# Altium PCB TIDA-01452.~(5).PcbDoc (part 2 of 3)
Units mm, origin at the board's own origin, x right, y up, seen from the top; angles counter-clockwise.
Board outline 60 x 40 mm, 6 copper layers (Top Layer, IN1-GND, IN2, IN3-POWER, IN4-GND, Bottom Layer), stack 1.532 mm thick; 266 components, 172 nets, 850 pads, 525 vias.

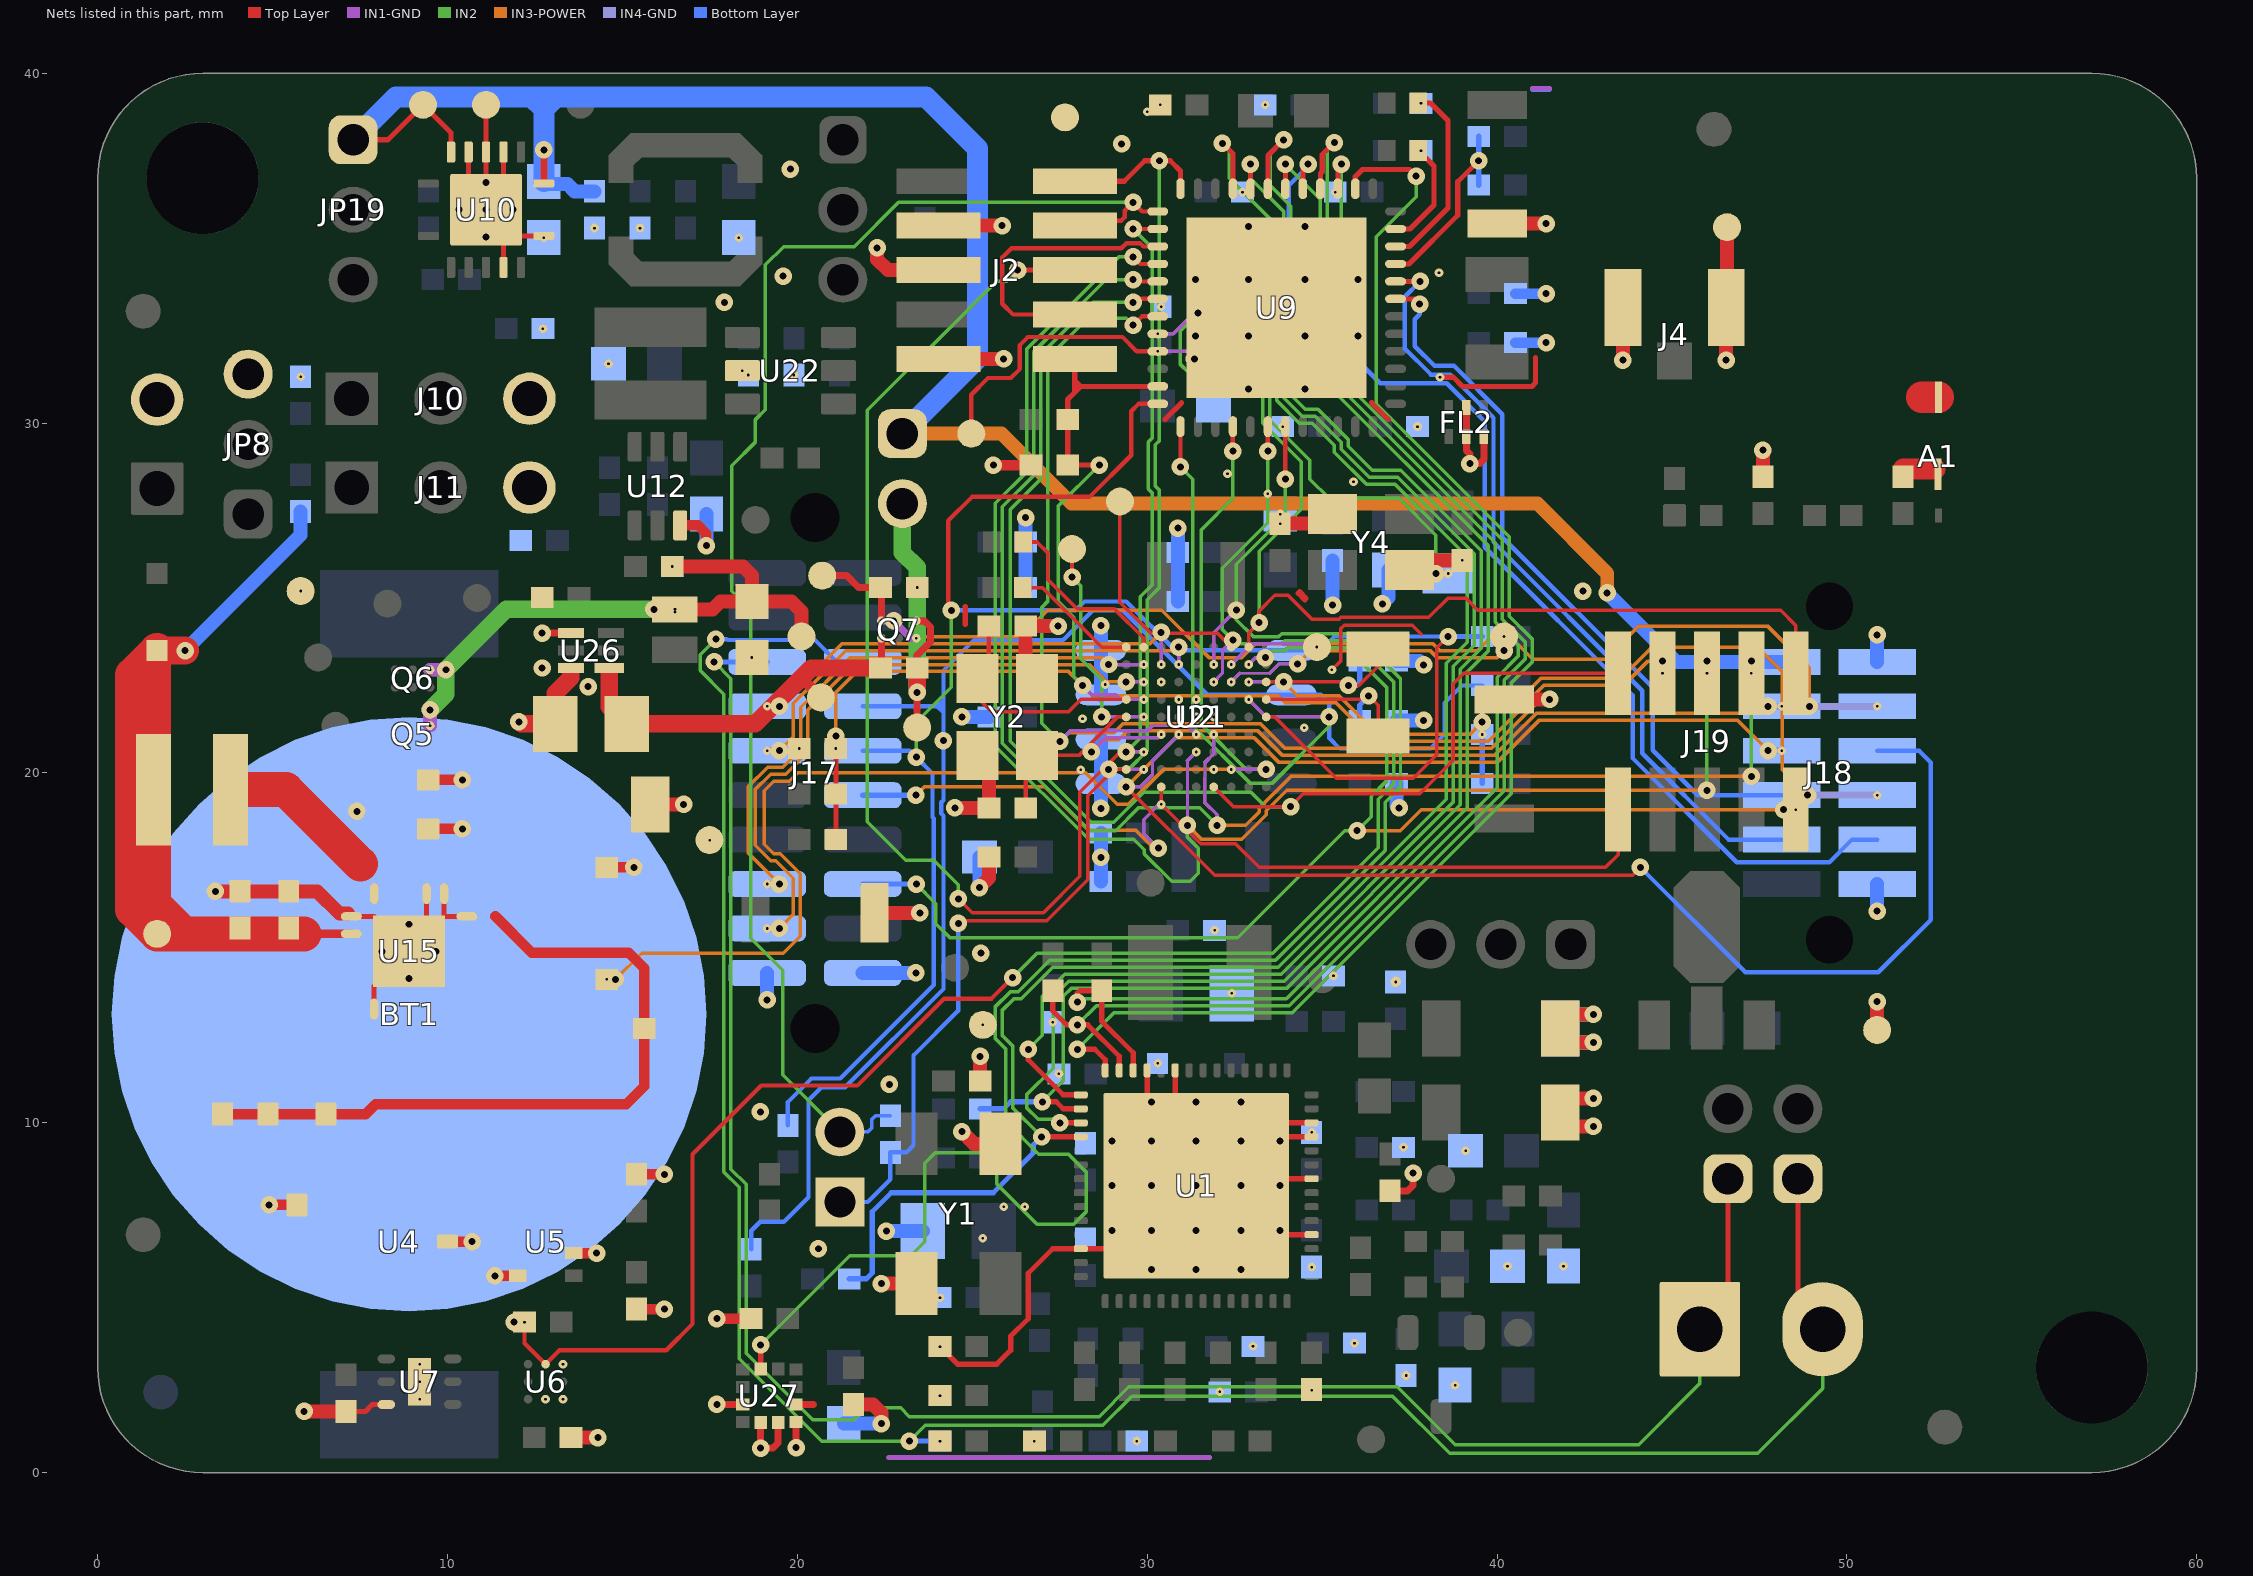
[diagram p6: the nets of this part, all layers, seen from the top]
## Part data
A1: "2.4GHz PCB Antenna.  There is nothing to buy or mount."
BT1: "Battery Holder, Retainer clip, SMT"
C1 C6: "CAP, CERM, 2.2 µF, 25 V, +/- 10%, X5R, 0402"
C2: "CAP, CERM, 2200 pF, 50 V, +/- 10%, X7R, 0402"
C3: "CAP, CERM, 0.47 µF, 16 V, +/- 10%, X5R, 0402"
C4 C9 C31 C32: "CAP, CERM, 1000 pF, 50 V, +/- 5%, C0G/NP0, 0402"
C5 C30 C35 C45 C47 C48 C49 C50 C51 C68 C84 C111 C112: "CAP, CERM, 0.1 µF, 50 V, +/- 10%, X7R, AEC-Q200 Grade 1, 0402"
C8: library part GRM1555C1H102JA01D, "CAP, CERM, 1000 pF, 50 V, +/- 5%, C0G/NP0, 0402"
C10 C14 C42 C43: "CAP, CERM, 16 pF, 50 V, +/- 5%, C0G/NP0, 0402"
C11: library part C1206C106K3RACTU, "DNI"
C12 C13: "CAP, CERM, 10 µF, 25 V, +/- 10%, X7R, 1206_190"
C15 C29: "CAP, CERM, 2.2 µF, 16 V, +/- 10%, X7R, 0805"
C16: "CAP, CERM, 100 pF, 50 V, +/- 5%, C0G/NP0, 0402"
C17: "CAP, CERM, 220 pF, 50 V, +/- 5%, C0G/NP0, 0402"
C18 C36 C37 C39 C40 C56 C57 C59 C61 C62 C71 C78 C80 C98 C100 C101: "CAP, CERM, 0.1 µF, 6.3 V, +/- 10%, X7R, 0402"
C19: "CAP, CERM, 390 pF, 50 V, +/- 5%, C0G/NP0, 0402"
C20 C21: "CAP, CERM, 0.22 µF, 16 V, +/- 10%, X7R, 0603"
C22: "CAP, CERM, 0.047 µF, 50 V, +/- 10%, X7R, 0402"
C23 C24: "CAP, CERM, 470 pF, 50 V, +/- 5%, C0G/NP0, 0402"
C25 C69: "CAP, CERM, 1 µF, 25 V, +/- 10%, X5R, 0402"
C26: "CAP, CERM, 33 pF, 50 V, +/- 5%, C0G/NP0, 0402"
C27 C34: "CAP, CERM, 0.022 µF, 50 V, +/- 10%, C0G/NP0, 0402"
C28: "CAP, CERM, 150 pF, 50 V, +/- 5%, C0G/NP0, 0402"
C33: "CAP, CERM, 0.01 µF, 50 V, +/- 10%, C0G/NP0, 0402"
C38 C58 C60 C75 C76 C85 C113: "CAP, CERM, 10 µF, 6.3 V, +/- 20%, X5R, 0603"
C41 C77 C79 C82: "CAP, CERM, 4.7 µF, 10 V, +/- 10%, X5R, 0402"
C44 C46 C65 C66: "CAP, CERM, 12 pF, 25 V, +/- 5%, C0G/NP0, 0402"
C55 C67 C110: library part C0402C103J5RACTU, "CAP, CERM, 0.01 µF, 50 V, +/- 5%, X7R, 0402"
C63 C64: library part GRM1555C1H9R0DA01D, "CAP, CERM, 9pF, 50V, +/- 0.5pF, C0G/NP0, 0402"
C70 C72: "CAP, CERM, 22 µF, 10 V, +/- 20%, X5R, 0603"
C81: "CAP, CERM, 0.01 µF, 50 V, +/- 5%, X7R, 0402"
C83: "CAP, CERM, 100 µF, 10 V, +/- 20%, X5R, 1206_190"
C86: "CAP, CERM, 10 µF, 10 V, +/- 10%, X7R, 0805"
CR1 CR3: "Red 621nm LED Indication - Discrete 1.8V 0402 (1005 Metric)"
CR2 CR4: "Green 569nm LED Indication - Discrete 1.9V 0402 (1005 Metric)"
D2 D4: "Diode, Schottky, 5V, 0.03A, SOD-323"
D3: "Diode, Schottky, 30 V, 0.2 A, SOD-323"
FL1: "Ferrite Bead, 1500 ohm @ 100 MHz, 0.5 A, 0603"
FL2: "Filter, BandPass, 2.45GHz, SMD"
J2 J19: "Header, 1.27mm, 5x2, Gold, SMT"
J4: library part U.FL-R-SMT-1, "Connector, Ultra-Mini Coaxial, SMD"
J5: "Terminal Block, 6A, 3.5mm Pitch, 2-Pos, TH"
J9: "Header, 100mil, 2x1, Tin, TH"
J10 J11: "Header, 100mil, 3x1, Tin, TH"
J17: "Receptacle, 50mil, 10x2, Gold, SMT"
J18: "Receptacle, 1.27mm, 6x2, Gold, SMT"
JP1 JP24 JP25 JP30: "Header, 2mm, 2x1, Tin, TH"
JP6 JP7 JP8 JP19: "Header, 2mm, 3x1, Tin, TH"
L1: "Inductor, Wirewound, 100 µH, 0.27 A, 1.4 ohm, SMD"
L2 L3: "Inductor, Multilayer, Ferrite, 4.7 µH, 0.3 A, 0.143 ohm, SMD"
L4: "Inductor, Multilayer, Ferrite, 10 µH, 0.11 A, 0.52 ohm, SMD"
L5: "Inductor, Shielded Drum Core, Ferrite, 10 µH, 1.25 A, 0.2 ohm, SMD"
L6: "Inductor, Shielded, Ferrite, 4.7 µH, 1.2 A, 0.14 ohm, SMD"
L7: "Inductor, Shielded Drum Core, Ferrite, 22uH, 0.5A, 0.525 ohm, SMD"
L8: "Inductor, Shielded, Ferrite, 4.7uH, 0.64A, 0.25 ohm, SMD"
Q1: library part "2SB1260T100R, Rohm", "Transistor, PNP, 80 V, 1 A, SOT-89"
Q4: library part "BC846BLT1G, ON Semiconductor", "Transistor, NPN, 65 V, 0.1 A, SOT-23"
Q5 Q6 Q7: "MOSFET, P-CH, -20 V, -1.6 A,"
R1: "RES, 20.0 k, 1%, 0.1 W, 0603"
R5: "RES, 402 k, 1%, 0.063 W, 0402"
R7 R15 R16 R24 R28 R44 R67: "RES, 100 k, 1%, 0.063 W, 0402"
R8: "RES, 4.02, 1%, 0.1 W, 0603"
R9: "RES, 8.25 k, 1%, 0.1 W, 0603"
R10: "RES, 5.11 k, 1%, 0.063 W, 0402"
R11: "RES, 30.1 k, 1%, 0.063 W, 0402"
R12: "RES, 1.10 k, 1%, 0.1 W, 0603"
R13 R14 R21 R22: "RES, 33.0 k, 0.1%, 0.063 W, 0402"
R17: "RES, 10.0, 1%, 0.1 W, 0603"
R18: "RES, 200 k, 1%, 0.063 W, 0402"
R19: "RES, 49.9 k, 1%, 0.063 W, 0402"
R20: "RES, 332 k, 1%, 0.063 W, 0402"
R23: "RES, 37.4 k, 1%, 0.063 W, 0402"
R25: "RES, 91.0 k, 0.1%, 0.1 W, 0603"
R26 R41 R45 R49 R56 R59 R68 R84 R87 R95 R100: library part CRCW04020000Z0ED, "RES, 0, 5%, 0.063 W, 0402"
R27 R31 R42 R43 R46 R54 R60 R80 R85 R86 R96 R118 R119 R122: "RES, 0, 5%, 0.063 W, 0402"
R29 R131 R132: library part CRCW0402100KFKED, "RES, 100 k, 1%, 0.063 W, 0402"
R30 R34 R39: "RES, 270, 1%, 0.0625W, 50V, 0402"
R32 R33 R37 R38: "RES, 680, 5%, 0.063 W, 0402"
R35 R36 R40 R109 R110: "RES, 10.0 k, 1%, 0.063 W, 0402"
R55 R93 R139: "RES, 1.00 M, 1%, 0.063 W, 0402"
R61: "RES, 6.65 M, 1%, 0.063 W, 0402"
R62: "RES, 2.37 M, 1%, 0.063 W, 0402"
R63 R90: "RES, 5.11 M, 1%, 0.063 W, 0402"
R64: "RES, 6.19 M, 1%, 0.063 W, 0402"
R65: "RES, 4.42 M, 1%, 0.063 W, 0402"
R88: "RES, 7.87 M, 1%, 0.063 W, 0402"
R89: "RES, 169 k, 1%, 0.063 W, 0402"
R91: library part CRCW04021M00FKED, "RES, 1.00 M, 1%, 0.063 W, 0402"
R140: "RES, 402, 1%, 0.063 W, 0402"
SW1 SW2 SW3: "SWITCH TACTILE SPST-NO 0.05A 12V"
TP1 TP2 TP4 TP5 TP6 TP8 TP9 TP10 TP11 TP12 TP13 TP14 TP15 TP16 TP18 TP19 TP20 TP21 TP22 TP23 TP24 TP25 TP26 TP27 TP28 TP29 TP30 TP32 TP33 TP34: library part TEST_POINT_ROUND_1.2, "Round Test Point, 1.2mm diam."
U1: "DAC8730, DAC8730"
U2: "Mixed-Signal Microcontroller, ZXH0080A"
U4: "Low Power, High Accuracy Digital Humidity Sensor with Temperature Sensor, DMB0006A"
U5: "Digital Pressure Sensor, LGA8-2X2_5MM_0_65"
U6: "Infrared Thermopile Sensor with Integrated Math Engine, YZF0008AEAE"
U7: "Ambient Light Sensor, DNP0006A"
U9: "SimpleLink Multistandard Wireless MCU, RGZ0048A"
U10: "Programmable Output Voltage Ultra-Low Power Buck Converter with up to 50mA / 200 mA Output Current, RGY0014A"
U12: "LOW INPUT VOLTAGE STEP-UP CONVERTER IN 6 PIN SC-70 PACKAGE, DCK0006A"
U15: "Ultra Low Power Boost Converter with Battery Management for Energy Harvester Applications, RGR0020A"
U21: "256K I2C CMOS Serial EEPROM"
U22: "1-Ohm SPDT ANALOG SWITCH 5-V/3.3-V SINGLE-CHANNEL 2:1 MULTIPLEXER/DEMULTIPLEXER, DBV0006A"
U26: "Ultra-Low Quiescent Current Synchronous Boost with Integrated LDO/Load Switch, DSE0006A"
U27: "Ultra-low-power high-performance 3-axis pico accelerometer"
Y1: "Crystal, 8 MHz, 10 pF, SMD"
Y2: "Crystal, 48MHz, 10pF, SMD"
Y3 Y5: "Crystal, 32.768 KHz, 7 pF, SMD"
Y4: "Crystal, 24 MHz, 9 pF, SMD"

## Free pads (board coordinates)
  round 3.2 hole 3.2 unplated paste-3.2 mask+0.075: 0(3,37) 0(57,3)

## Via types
v1: diameter 0.4/0.5/0.5/0.5/0.5/0.4 (per signal layer), hole 0.2, Top Layer to Bottom Layer, 266 vias
v2: diameter 0.25/0.25 (per signal layer), hole 0.075, Top Layer to IN1-GND, tented top, 102 vias
v3: diameter 0.5/0.5/0.5/0.5 (per signal layer), hole 0.2, IN1-GND to IN4-GND, 75 vias
v4: diameter 0.25/0.25 (per signal layer), hole 0.075, IN4-GND to Bottom Layer, tented bottom, 55 vias
v5: diameter 0.5, hole 0.2, Top Layer to Bottom Layer, 21 vias
v6: diameter 0.25/0.2 (per signal layer), hole 0.075, Top Layer to IN1-GND, tented top, 5 vias
v7: diameter 0.3, hole 0.075, IN4-GND to Bottom Layer, 1 vias

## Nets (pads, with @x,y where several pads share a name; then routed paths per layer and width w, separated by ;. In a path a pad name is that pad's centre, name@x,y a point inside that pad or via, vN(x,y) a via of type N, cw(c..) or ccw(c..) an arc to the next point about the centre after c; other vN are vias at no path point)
ANA_SSM.ANA1_1: J17.7 U2.C8 | length 13.1
  IN1-GND w0.1: v2(30.4,23.1) v3(30.4,24.02)
  IN3-POWER w0.1: v3(19.485,21.905) 21.28,23.7 30.08,23.7 v3(30.4,24.02)
  IN4-GND w0.2: v4(19.135,21.905) v3(19.485,21.905)
ANA_SSM.ANA2_1: J17.9 U2.D8 | length 14
  IN1-GND w0.1: v2(30.9,23.1) v3(30.9,23.6)
  IN3-POWER w0.1: v3(19.485,20.635) 19.885,21.035 19.885,21.985 21.4,23.5 30.8,23.5 v3(30.9,23.6)
  IN4-GND w0.2: v4(19.135,20.635) v3(19.485,20.635)
BQ25505_VBAT_OK: R60.1 U2.G2 U9.40 | length 38.4
  Top Layer w0.125: v1(32.45,29.2) U9.40@32.45,29.9
  IN1-GND w0.1: v2(32.4,20.1) v3(33.4,20.1)
  IN1-GND w0.2: v2(14.55,14.1) v3(14.8,14.1)
  IN2 w0.1: v1(32.45,29.2) 32.45,27.849 31.55,26.949 31.55,21.384 32.834,20.1 v3(33.4,20.1)
  IN3-POWER w0.1: v3(14.8,14.1) 15.55,14.85 19.6,14.85 20.085,15.335 20.085,17.115 19.505,17.695 19.319,17.695 19.05,17.964 19.05,19.496 19.319,19.765 19.765,19.765 20,20 28.241,20 29.141,19.1 29.466,19.1 30.466,20.1 v3(33.4,20.1)
BUS+: J5.2 J17.6 JP24.1 R19.1 | length 66.8
  Top Layer w0.15: JP24.1@48.6,8.4 48.6,4.805 J5.2@49.305,4.1
  IN2 w0.1: v1(17.67,23.825) 17.22,23.375 17.22,22.93 17.9,22.25 17.9,8.593 18.338,8.156 18.338,3.259 20.696,0.9 v1(23.2,0.9) 23.65,1.35 28.521,1.35 28.729,1.35 29.566,2.188 37.012,2.188 38.65,0.55 47.45,0.55 49.305,2.405 J5.2@49.305,4.1
  Bottom Layer w0.125: v1(17.67,23.825) 17.985,23.825 18.01,23.8 20.5,23.8 21.125,23.175 J17.6@21.865,23.175
  Bottom Layer w0.15: v1(23.2,0.9) R19.1@24.075,0.9
BUS-: J5.1 J17.5 JP25.1 | length 57.9
  Top Layer w0.15: J5.1@45.8,4.1 46.6,4.9 JP25.1@46.6,8.4
  IN2 w0.1: v1(17.62,23.175) 18.1,22.695 18.1,8.676 18.538,8.238 18.538,3.412 20.44,1.51 21.61,1.51 21.95,1.85 22.95,1.85 23.2,1.6 28.625,1.6 29.475,2.45 37.15,2.45 38.8,0.8 44.05,0.8 45.8,2.55 J5.1@45.8,4.1
  Bottom Layer w0.15: v1(17.62,23.175) J17.5@19.135,23.175
CC2650_BSL: J18.10 U9.17 | length 31.6
  Top Layer w0.15: U9.17@34.45,36.7 34.45,37.25 v1(34.6,37.4)
  Bottom Layer w0.125: v1@34.6,37.35 34.05,36.8 34.05,33.75 36.662,31.138 38.561,31.138 39.65,30.048 39.65,26.45 43.875,22.225 43.875,20.425 46.85,17.45 49.5,17.45 50.145,18.095 J18.10@50.865,18.095
CC2650_BUTTON_4: R39.2 R40.2 U9.9 | length 5.6
  Top Layer w0.15: U9.9@37.1,34.55 37.484,34.55 38.875,35.941 38.875,36.9 v1(39.475,37.5)
  Bottom Layer w0.15: R40.2@39.475,36.8 v1(39.475,37.5) R39.2@39.475,38.2
CC2650_DAC8730_IRQ: R131.2 U1.26 U9.16 | length 40.7
  Top Layer w0.15: v1(28,13.45) 28,13.7 28.075,13.775 R131.2@28.7,13.775 28.7,12.9 29.6,12 U1.26@29.6,11.5 ; U9.16@34.95,36.7 34.95,37.134 35,37.184 35,37.67 v1(35.35,38.02)
  IN2 w0.1: v1(28,13.45) 28.1,13.55 33.98,13.55 40.004,19.574 40.004,22.739 40.6,23.334 40.6,23.666 39.95,24.316 39.95,26.584 35.15,31.384 35.15,37.82 v1(35.35,38.02)
CC2650_DAC8730_SPI_CLK: U1.29 U9.20 | length 40.5
  Top Layer w0.15: v1(26.6,12.1) 26.6,11.8 27.6,10.8 U1.29@28.1,10.8 ; U9.20@32.95,36.7 v1(32.95,37.4)
  IN2 w0.1: v1(26.6,12.1) 27,12.5 27,13.61 27.64,14.25 33.831,14.25 38.75,19.169 38.75,23.051 39.35,23.651 39.35,26.266 37.166,28.45 36.351,28.45 35.55,29.251 35.55,29.449 34.799,30.2 34.43,30.2 33.9,30.73 33.9,36.05 32.95,37 v1(32.95,37.4)
CC2650_DAC8730_SPI_CS: R29.2 U1.32 U9.21 | length 52.7
  Top Layer w0.15: v1(26.98,9.6) U1.32@28.1,9.6 ; v1(32.15,38) 32.45,37.7 U9.21@32.45,36.7
  IN2 w0.1: v1(26.98,9.6) 26.15,10.43 26.15,12.203 25.85,12.503 25.85,13.21 26.19,13.55 26.399,13.55 27.299,14.45 33.749,14.45 38.55,19.251 38.55,23.134 39.15,23.734 39.15,26.183 37.083,28.25 36.269,28.25 35.35,29.169 35.35,29.366 34.716,30 34.347,30 33.7,30.647 33.7,35.65 32.35,37 32.35,37.8 v1(32.15,38)
  Bottom Layer w0.15: R29.2@21.483,5.539 21.97,5.539 22.14,5.709 22.14,7.457 22.683,8 25.6,8 26.74,9.14 26.74,9.36 v1(26.98,9.6)
CC2650_DAC8730_SPI_MISO: R28.2 U1.30 U9.18 | length 41.8
  Top Layer w0.15: v1(27,10.6) 27.4,10.6 27.6,10.4 U1.30@28.1,10.4 ; U9.18@33.95,36.7 v1(33.95,37.4)
  IN2 w0.1: v1(27,10.6) 27.6,11.2 27.6,13.616 27.834,13.85 33.997,13.85 39.15,19.003 39.15,22.886 39.75,23.486 39.75,26.501 34.95,31.301 34.95,36.4 v1(33.95,37.4)
  Bottom Layer w0.15: R28.2@25.225,10.4 25.9,10.4 26.1,10.6 v1(27,10.6)
CC2650_DAC8730_SPI_MOSI: U1.31 U9.19 | length 43.3
  Top Layer w0.15: v1(27.5,10) U1.31@28.1,10 ; U9.19@33.45,36.7 33.45,37.65 v1(33.9,38.1)
  IN2 w0.1: v1(27.5,10) 27.4,10.1 26.881,10.1 26.562,10.419 26.562,10.812 27.312,11.562 27.312,13.611 27.751,14.05 33.914,14.05 38.95,19.086 38.95,22.969 39.55,23.569 39.55,26.349 37.249,28.65 36.434,28.65 35.75,29.334 35.75,29.531 34.881,30.4 34.513,30.4 34.1,30.813 34.1,36.204 33.512,36.791 33.512,37.712 v1(33.9,38.1)
CC2650_DAC8730_UART_RX: R132.2 U1.27 U9.15 | length 39.5
  Top Layer w0.15: R132.2@27.3,13.775 27.3,13.2 27.7,12.8 v1(28,12.8) 28.3,12.8 29.2,11.9 U1.27@29.2,11.5 ; U9.15@35.45,36.7 35.45,37.3 v1(35.55,37.4)
  IN2 w0.1: v1(28,12.8) 28.55,13.35 34.063,13.35 40.204,19.492 40.204,22.656 40.8,23.251 40.8,23.749 40.15,24.399 40.15,26.667 35.55,31.267 v1(35.55,37.4)
CC2650_DAC8730_UART_TX: U1.28 U9.14 | length 39.1
  Top Layer w0.15: v1(28,12.1) 28.5,12.1 28.8,11.8 U1.28@28.8,11.5 ; U9.14@35.95,36.7 35.95,37.05 36.15,37.25 37.5,37.25 v1(37.69,37.06)
  IN2 w0.1: v1(28,12.1) 29.05,13.15 34.146,13.15 40.404,19.409 40.404,22.573 41,23.169 41,23.831 40.35,24.481 40.35,26.75 36.55,30.55 36.55,35.331 37.69,36.471 v1(37.69,37.06)
CC2650_FTDI_UART_RX: J18.7 U9.7 | length 20.9
  Top Layer w0.15: U9.7@37.1,33.55 37.64,33.55 v1(37.79,33.4)
  Bottom Layer w0.125: v1(37.79,33.4) 37.79,33.11 37.65,32.97 37.65,32.2 38.212,31.638 38.768,31.638 40.15,30.255 40.15,26.739 44.45,22.439 44.45,20.65 45.735,19.365 J18.7@48.135,19.365
CC2650_FTDI_UART_TX: J18.9 U9.8 | length 22.5
  Top Layer w0.15: U9.8@37.1,34.05 v1(37.8,34.05)
  Bottom Layer w0.125: v1(37.8,34.05) 37.362,33.612 37.362,32.134 38.109,31.388 38.664,31.388 39.9,30.152 39.9,26.6 44.15,22.35 44.15,20.561 46.616,18.095 J18.9@48.135,18.095
CC2650_GPS_I2C_SCL: J17.8 R109.2 R119.1 U2.H6 U9.37 U21.6 | length 58.8
  Top Layer w0.125: v1(30.95,28.75) U9.37@30.95,29.9
  IN1-GND w0.1: v2(32.9,22.1) 33.4,21.6 v1(35.2,21.6)
  IN2 w0.1: v1(30.95,28.75) 31.3,28.4 31.3,21.351 32.951,19.7 33.566,19.7 35.2,21.334 v1(35.2,21.6)
  Bottom Layer w0.125: R119.1@18.68,6.381 18.68,6.911 18.936,7.167 19.615,7.167 20.319,7.872 20.319,10.644 20.689,11.014 21.364,11.014 24.175,13.825 24.175,18.777 24.112,18.839 24.112,19.161 24.175,19.223 v1(24.175,20.925) 24.175,21.73 ; J17.8@21.865,21.905 24,21.905 ; R109.2@39.575,22.5 39,22.5 38.5,22 38.5,21.1 38.1,20.7 35.5,20.7 35.2,21 v1(35.2,21.6) 35.2,22 34.965,22.235 U21.6@34.125,22.235 31.715,22.235 29.3,24.65 28.45,24.65 27.6,23.8 25.05,23.8 24.175,22.925 24.175,22.08 ; 24,21.905 24.175,22.08 ; 24,21.905 24.175,21.905 ; 24,21.905 24.175,21.73 ; 24.175,21.73 24.175,21.905 ; 24.175,21.905 24.175,22.08
CC2650_GPS_I2C_SDA: J17.10 R110.2 R118.1 U2.J5 U9.36 U21.5 | length 55.3
  Top Layer w0.1: U2.J5@33.4,21.6 33.65,21.6 35.4,19.85 37.6,19.85 38.275,20.525 38.275,23.575 v1(38.6,23.9)
  Top Layer w0.125: v1(24.4,24.65) 24.307,24.743 24.307,27.207 24.99,27.89 28.35,27.89 29.54,29.08 29.54,30.34 29.75,30.55 U9.36@30.3,30.55
  IN2 w0.1: v1(23.4,20.45) 23.4,21.45 24.4,22.45 v1(24.4,24.65)
  Bottom Layer w0.125: R118.1@19.73,9.925 19.73,10.593 20.401,11.264 21.225,11.264 23.9,13.939 23.9,18.698 23.862,18.736 23.862,19.988 v1(23.4,20.45) 23.215,20.635 J17.10@21.865,20.635 ; v1(24.4,24.65) 27.955,24.65 28.205,24.9 29.404,24.9 30.799,23.505 U21.5@34.125,23.505 34.955,23.505 35.35,23.9 v1(38.6,23.9)
  Bottom Layer w0.15: v1(38.6,23.9) R110.2@39.575,23.9
CC2650_GPS_LIS_IRQ: U2.F8 U9.43 U27.12 | length 53.8
  Top Layer w0.125: v1(33.95,28.4) U9.43@33.95,29.9
  Top Layer w0.15: U27.12@18.95,2.963 v1(18.95,3.65)
  IN1-GND w0.1: v2(31.9,23.1) 31.9,24.007 v3(32.55,24.657)
  IN2 w0.1: v1(18.95,3.65) 21.501,6.201 23.239,6.201 23.64,6.602 23.64,8.848 23.942,9.15 25.366,9.15 25.7,8.816 25.7,8.25 26.85,7.1 27.9,7.1 28.25,7.45 28.25,8.6 27.75,9.1 26.9,9.1 25.95,10.05 25.95,12.12 25.65,12.42 25.65,13.31 26.09,13.75 26.316,13.75 27.216,14.65 33.666,14.65 36.8,17.784 36.8,19.166 37.24,19.606 37.24,22.693 35.953,23.98 33.844,23.98 33.764,23.9 33.034,23.9 32.55,24.384 v3(32.55,24.657) 32.55,25.969 33.95,27.369 v1(33.95,28.4)
CC2650_GPS_TMP_IRQ: R36.2 U2.F7 U6.C2 U9.42 | length 52.8
  Top Layer w0.125: v2(12.2,4.3) 12.2,3.7 U6.C2@12.8,3.1 13.2,3.5 16.25,3.5 17,4.25 17,9.1 18.965,11.065 21.715,11.065 24.2,13.55 25.55,13.55 v1(26.15,14.15) ; v1(33.45,29.2) U9.42@33.45,29.9
  IN1-GND w0.082: 32.15,22.85 32.15,23.5
  IN1-GND w0.1: v2(31.9,22.6) 32.15,22.85 ; 32.15,23.5 v3(32.45,23.8)
  IN1-GND w0.2: v3(11.9,4.3) v2(12.2,4.3)
  IN2 w0.1: v1(26.15,14.15) 26.85,14.85 33.583,14.85 36.6,17.867 36.6,19.249 37.04,19.689 37.04,22.61 35.87,23.78 33.927,23.78 33.847,23.7 32.55,23.7 v3(32.45,23.8) 32.15,24.1 32.15,25.851 33.45,27.151 v1(33.45,29.2)
CC2650_JTAG_TCK: J2.4 JP1.2 R100.2 U9.25 | length 42.4
  Top Layer w0.125: J2.4@27.93,35.645 28.075,35.79 29.26,35.79 29.36,35.89 29.36,36.07 v1(29.6,36.31) 29.86,36.05 U9.25@30.3,36.05
  IN2 w0.1: JP1.2@21.215,9.737 19.577,11.375 19.577,14.364 18.661,15.279 18.661,24.661 18.124,25.198 18.124,28.783 18.802,29.461 18.802,30.103 19.085,30.386 19.085,34.523 19.607,35.046 21.626,35.046 22.891,36.31 v1(29.6,36.31)
  Bottom Layer w0.1: JP1.2@21.215,9.737 22.013,9.737 22.126,9.85 22.126,10.095 22.234,10.204 R100.2@22.656,10.204
CC2650_JTAG_TDI: J2.8 U9.27 | length 8.2
  Top Layer w0.125: J2.8@27.93,33.105 26.165,33.105 25.857,33.413 25.857,34.737 26.12,35 29.26,35 29.398,35.138 29.802,35.138 29.89,35.05 U9.27@30.3,35.05
CC2650_JTAG_TDO: U2.B3 U9.26 | length 16.8
  Top Layer w0.125: v1(29.6,35.55) U9.26@30.3,35.55
  IN1-GND w0.1: v3(29.4,20.6) v2(29.9,20.6)
  IN2 w0.1: v3(29.4,20.6) 29.8,21 29.8,25.033 30.15,25.383 30.15,27.999 30.031,28.118 30.031,29.46 30.15,29.579 30.15,35 v1(29.6,35.55)
CC2650_JTAG_TMS: J2.2 U2.B2 U9.24 | length 23.3
  Top Layer w0.15: J2.2@27.93,36.915 29.345,36.915 29.93,37.5 v1(30.35,37.5) 30.66,37.5 30.95,37.21 U9.24@30.95,36.7
  IN1-GND w0.1: v3(28.9,20.1) v2(29.9,20.1)
  IN2 w0.1: v3(28.9,20.1) 29.466,20.1 30,20.634 30,24.95 30.35,25.3 30.35,28.082 30.231,28.201 30.231,29.377 30.35,29.496 v1(30.35,37.5)
CC2650_LED1_4: CR3.2 U9.10 | length 5.5
  Top Layer w0.15: U9.10@37.1,35.05 37.5,35.05 38.6,36.15 38.6,38.65 38.1,39.15 CR3.2@37.75,39.15
CC2650_LED2_4: CR4.2 U9.11 | length 3.1
  Top Layer w0.15: U9.11@37.1,35.55 37.511,35.55 38.2,36.239 38.2,37.35 CR4.2@37.75,37.8
CC2650_NRESET: C45.1 C68.1 J2.10 J18.8 R24.2 R30.1 R44.2 U2.B6 U9.35 | length 55.3
  Top Layer w0.15: R30.1@21.1,18.1 v2(21.1,20.7) ; C68.1@27.725,28.8 R44.2@27.725,30.1 27.725,30.675 27.93,30.88 ; C68.1@27.8,28.8 v1(28.63,28.8) ; J2.10@27.93,31.835 27.93,31.22 ; U9.35@30.3,31.05 28.1,31.05 ; 27.93,30.88 28.1,31.05 ; 27.93,30.88 27.93,31.22 ; 27.93,31.22 28.1,31.05
  IN1-GND w0.1: v3(28.15,22.5) 28.42,22.23 29.103,22.23 29.233,22.1 v2(29.9,22.1)
  IN1-GND w0.2: v2(21.1,20.7) v3(21.1,21.05)
  IN2 w0.1: v3(28.15,22.5) 27.9,22.75 27.9,24.45 27.45,24.9 27.45,27.62 v1(28.63,28.8)
  IN3-POWER w0.1: v3(21.1,21.05) 21.1,22.3 21.7,22.9 27.75,22.9 v3(28.15,22.5) 28.45,22.2 33.75,22.2 33.95,22 35.4,22 36.5,20.9 39.75,20.9 40.9,22.05 40.9,22.349 41.251,22.7 43.533,22.7 44.433,23.6 47.436,23.6 48.15,22.886 48.15,20.095 v3(48.88,19.365)
  IN4-GND w0.2: v3(48.88,19.365) v4(50.865,19.365)
CC2650_SSM_IRQ: J19.10 U2.H9 U9.32 | length 32.3
  Top Layer w0.1: U2.H9@32.9,23.6 32.9,24 v1(33.2,24.3) 33.2,24.63 33.645,25.075 34.025,25.075 34.7,24.4 35.484,24.4 35.534,24.45 38.05,24.45 38.6,25 39.1,25 39.45,24.65 48.105,24.65 48.54,24.215 J19.10@48.54,22.85
  IN1-GND w0.1: v2(30.3,32.55) 30.75,32.55 31.35,33.15 v3(31.45,33.15)
  IN2 w0.1: v3(31.45,33.15) 31.45,33.137 30.95,32.637 30.95,31.674 31.184,31.44 32.997,31.44 33.3,31.137 33.3,30 34.4,28.9 34.4,27.536 33.2,26.336 v1(33.2,24.3)
CC2650_SSM_SPI_CLK: J19.2 U2.F1 U9.30 | length 39.6
  Top Layer w0.1: U2.F1@31.9,19.6 32.46,19.04 v1(34.1,19.04) 34.46,19.4 37.786,19.4 38.75,20.364 38.75,22.55 39.05,22.85 J19.2@43.46,22.85
  Top Layer w0.125: v1(29.6,33.45) 29.7,33.55 U9.30@30.3,33.55
  IN2 w0.1: v1(29.6,33.45) 28.45,33.45 26.95,31.95 26.95,28.4 26.08,27.53 26.08,20.91 28.4,18.59 29.04,18.59 29.9,19.45 32.966,19.45 33.376,19.04 v1(34.1,19.04)
CC2650_SSM_SPI_CS: J19.4 U2.E4 U9.31 | length 38.5
  Top Layer w0.125: v1(29.6,32.8) 29.85,33.05 U9.31@30.3,33.05
  IN1-GND w0.082: 30.15,21.35 31.15,21.35
  IN1-GND w0.1: v3(27.5,20.9) 27.8,21.2 30,21.2 30.15,21.35 ; 31.15,21.35 v2(31.4,21.1)
  IN1-GND w0.2: v2(44.73,22.85) v3(44.73,23.2)
  IN2 w0.1: v3(27.5,20.9) 26.98,21.42 26.98,24.73 27.15,24.9 27.15,31.85 28.3,33 29.4,33 v1(29.6,32.8)
  IN3-POWER w0.1: v3(27.5,20.9) 27.75,21.15 29.051,21.15 29.301,21.4 33.25,21.4 33.95,20.7 39.833,20.7 41.1,21.967 41.1,22.266 41.334,22.5 43.616,22.5 44.316,23.2 v3(44.73,23.2)
CC2650_SSM_SPI_MISO: J19.6 U2.E3 U9.28 | length 47.6
  Top Layer w0.125: v1(29.6,34.75) 29.8,34.55 U9.28@30.3,34.55
  IN1-GND w0.082: v3(31.15,18.5) 31.15,20.35
  IN1-GND w0.1: 31.15,20.35 v2(31.4,20.6)
  IN1-GND w0.2: v2(46,22.85) v3(46,23.2)
  IN2 w0.1: v1(29.6,34.75) 29.184,34.75 26.55,32.116 26.55,28.6 25.66,27.71 25.66,20.764 28.324,18.1 29.616,18.1 29.916,17.799 29.916,17.684 30.701,16.9 31.225,16.9 31.459,17.134 31.459,17.853 31.15,18.162 v3(31.15,18.5) ; v3(46,19.5) v3(46,23.2)
  IN3-POWER w0.1: v3(31.15,18.5) 31.55,18.1 32.699,18.1 33.4,18.801 33.4,18.916 33.984,19.5 v3(46,19.5)
CC2650_SSM_SPI_MOSI: J19.8 U2.F4 U9.29 | length 46
  Top Layer w0.125: v1(29.6,34.1) 29.65,34.05 U9.29@30.3,34.05
  IN1-GND w0.082: 31.65,19.85 31.65,20.3
  IN1-GND w0.1: 31.65,19.85 31.65,19.15 32,18.8 v3(32,18.5) ; 31.65,20.3 31.9,20.55 v2(31.9,21.1)
  IN1-GND w0.2: v2(47.27,22.85) v3(47.27,23.2)
  IN2 w0.1: v1(29.6,34.1) 28.817,34.1 26.75,32.033 26.75,28.5 25.86,27.61 25.86,20.847 28.357,18.35 29.1,18.35 29.75,19 31.5,19 v3(32,18.5) ; v3(47.27,19.9) v3(47.27,23.2)
  IN3-POWER w0.1: v3(32,18.5) 32.816,18.5 33.2,18.884 33.2,18.999 34.101,19.9 v3(47.27,19.9)
DCDC_SW: L4.1 TP33.1 U9.33 | length 20.3
  Top Layer w0.125: TP33.1@24.97,29.7 24.97,30.81 25.45,31.29 26.1,31.29 26.36,31.55 26.36,32.23 26.59,32.46 29.29,32.46 29.7,32.05 v2(30.3,32.05)
  IN1-GND w0.1: v2(30.3,32.05) 31.14,32.05 v3(31.35,31.84)
  IN2 w0.1: v3@31.35,31.85 32.9,31.85 33.5,31.25 33.5,30.084 34.65,28.934 34.65,28.4 35.2,27.85 37.2,27.85 38.25,26.8 v3(38.25,25.7)
  IN4-GND w0.2: v3(38.25,25.7) v4(38.6,25.7)
EH_NEN: J18.4 Q7.A2 Q7.C1 R139.2 TP2.1 | length 35.8
  Top Layer w0.2: TP2.1@20.71,25.64 21.41,25.64 21.75,25.3 R139.2@22.375,25.3 ; v2(22.4,24.35) R139.2@22.4,25.3
  IN1-GND w0.2: v2(22.4,24.35) v3(22.75,24.35) 23.25,23.85 v2(23.4,23.85)
  IN3-POWER w0.1: v3(22.75,24.35) 23.2,23.9 26.4,23.9 27.15,24.65 30.416,24.65 31.766,23.3 32.7,23.3 33.1,23.7 38.167,23.7 38.367,23.5 39.45,23.5 39.85,23.9 40.366,23.9 41.016,23.25 43.1,23.25 44.05,24.2 47.733,24.2 48.93,23.003 v3(48.93,21.905)
  IN4-GND w0.2: v3(48.93,21.905) v4(50.865,21.905)
EH_VIN_7: C79.1 C80.1 D2.1 L7.1 R49.1 TP25.1 U15.2 | length 28.8
  Top Layer w0.25: 5.9,15.4 U15.2@7.25,15.4
  Top Layer w0.8: v1(2.5,23.5) D2.1@1.7,23.5 1.7,16.3 2.6,15.4
  Top Layer w1: D2.1@1.7,23.5 1,22.8 1,16.1 TP25.1@1.7,15.4 2.6,15.4 5.9,15.4
  Bottom Layer w0.4: v1(2.5,23.5) 5.8,26.8 R49.1@5.8,27.475
EH_VOUT_7: C85.1 L8.1 Q5.A1 Q6.A1 R140.2 TP29.1 | length 17.2
  Top Layer w0.4: R140.2@16.425,25.9 18.45,25.9 18.7,25.65 C85.1@18.7,24.9 ; v2(16.5,24.675) 17.575,24.675 17.8,24.9 C85.1@18.7,24.9 ; TP29.1@20.12,23.9 20.12,24.61 19.83,24.9 C85.1@18.7,24.9
  IN1-GND w0.4: v2(9.5,21.35) v3(9.5,21.8) ; v2(9.5,22.95) v3(9.95,22.95) ; v3(15.9,24.675) v2(16.5,24.675)
  IN2 w0.5: v3(9.5,21.8) 9.95,22.25 v3(9.95,22.95) 11.675,24.675 v3(15.9,24.675)
EH_VOUT_REG_6: C86.2 Q7.C2 R68.1 TP30.1 U26.1 | length 11.4
  Top Layer w0.2: 14.625,22.86 U26.1@14.625,23 ; R68.1@22.4,23 Q7.C2@22.4,23.85
  Top Layer w0.3: 20.11,22.72 TP30.1@20.67,22.16
  Top Layer w0.5: 14.625,22.86 14.625,21.891 C86.2@15.116,21.4 18.79,21.4 20.39,23 R68.1@22.375,23 R68.1@22.4,23
FTDI_UART1.RX_1: J18.5 U2.D4 | length 22.8
  IN1-GND w0.082: 30.15,19.946 30.15,20.35
  IN1-GND w0.1: v3(29.4,19.6) 29.804,19.6 30.15,19.946 ; 30.15,20.35 v2(30.9,21.1)
  IN3-POWER w0.1: v3(29.4,19.6) 30.8,21 33.066,21 33.766,20.3 39.999,20.3 41.199,21.5 46.885,21.5 v3(47.75,20.635)
  IN4-GND w0.2: v3(47.75,20.635) v4(48.135,20.635)
FTDI_UART1.TX_1: J18.3 U2.C4 | length 23.1
  IN1-GND w0.1: v3(28.4,20.6) 28.8,21 30.3,21 v2(30.4,21.1)
  IN3-POWER w0.1: v3(28.4,20.6) 28.75,20.95 29.184,20.95 29.434,21.2 33.167,21.2 33.867,20.5 39.916,20.5 41.116,21.7 47.545,21.7 v3(47.75,21.905)
  IN4-GND w0.2: v3(47.75,21.905) v4(48.135,21.905)
GND: A1.2 A1.3 BT1.1 C1.2 C2.2 C3.2 C4.2 C5.2 C6.2 C8.2 C9.2 C10.1 C11.2 C12.2 C13.2 C14.1 C15.1 C18.2 C19.2 C20.2 C21.2 C25.2 C26.2 C29.2 C30.2 C31.2 C33.2 C34.2 C35.2 C36.2 C37.2 C38.2 C39.2 C40.2 C41.2 C42.2 C43.2 C44.1 C45.2 C46.1 C47.2 C48.2 C49.2 C50.2 C51.2 C55.2 C56.2 C57.2 C58.2 C59.2 C60.2 C61.2 C62.1 C63.2 C64.2 C65.2 C66.2 C67.2 C68.2 C69.2 C70.2 C71.1 C72.2 C75.2 C76.2 C77.2 C78.2 C79.2 C80.2 C81.2 C82.2 C83.2 C84.2 C85.2 C86.1 C98.2 C100.2 C101.1 C110.2 C111.2 C112.2 C113.2 D3.2 FL2.2 FL2.5 FL2.6 J2.3 J2.5 J2.9 J4.2 J4.3 J9.2 J10.3 J11.3 J17.19 J17.20 J18.2 J18.12 JP8.3 R7.2 R11.1 R12.2 R17.1 R25.1 R26.2 R32.1 R33.1 R37.1 R38.1 R45.1 R56.2 R59.2 R63.1 R65.1 R67.2 R85.2 R87.1 R90.1 R93.1 R122.2 R139.1 SW1.1 SW2.1 SW3.1 TP9.1 TP10.1 TP15.1 TP19.1 TP23.1 TP26.1 TP34.1 U1.4 U1.8 U1.11 U1.12 U1.23 U1.25 U1.40 U1.57 U2.C7 U2.D6 U2.E5 U2.E6 U2.F2 U2.F5 U4.2 U5.1 U5.7 U6.A1 U6.A2 U6.C1 U7.3 U7.7 U9.49 U10.3 U10.4 U10.5 U10.12 U10.14 U10.15@11.1,36.1 U12.3 U15.1 U15.6 U15.15 U15.16 U15.17 U15.21 U21.1 U21.2 U21.3 U21.4 U22.2 U26.4 U26.6 U27.3 U27.5 U27.6 U27.7 U27.8 Y1.2 Y1.4 Y2.2 Y2.4 Y4.2 Y4.4 | length 192.6
  Top Layer w0.1: v6(35.28,22.95) 35.525,23.195 35.525,24.122 35.628,24.225 37.572,24.225 37.837,23.96
  Top Layer w0.15: C51.2@7.1,1.75 7.65,1.75 7.845,1.945 U7.3@8.25,1.945 ; U15.1@7.25,15.9 7.9,15.9 U15.21@8.9,14.9 ; U15.6@7.9,13.25 7.9,13.9 U15.21@8.9,14.9 ; U15.17@9.4,16.55 U15.21@9.4,15.4 ; U15.16@9.9,16.55 U15.21@9.9,15.9 ; U15.15@10.55,15.9 U15.21@9.9,15.9 ; U10.5@10.6,37.75 10.6,36.6 v1(11.1,36.1) ; TP19.1@11.1,39.1 U10.4@11.1,37.75 v1(11.1,36.1) ; U10.12@11.6,34.45 U10.15@11.6,35.6 ; U10.3@11.6,37.75 11.6,36.6 v1(11.1,36.1) ; U10.14@12.75,35.35 11.85,35.35 U10.15@11.6,35.6 ; v2(24.075,3.6) 24.575,3.1 25.7,3.1 26.1,3.5 26.1,3.9 26.6,4.4 26.6,5.7 27.3,6.4 U1.40@28.1,6.4 29.6,6.4 v5(30.12,6.92) v5(31.4,8.2) ; 24.8,24.25 24.8,24.75 ; U1.25@30,11.5 30,9.6 v5(30.12,9.48) U1.57@30.8,8.8 ; 30.513,30.112 30.98,30.579 ; U1.23@30.8,11.5 U1.57@30.8,8.8 ; 34.319,25.14 34.511,24.948 ; 34.35,25.182 34.542,24.99 ; U1.4@34.7,6.8 32.8,6.8 v5(32.68,6.92) v5(31.4,8.2) ; U1.8@34.7,8.4 U1.57@31.6,8.4 ; U1.11@34.7,9.6 U1.57@32.8,9.6 ; U1.12@34.7,10 33.2,10 U1.57@32.8,9.6 ; 36.42,30.579 36.887,30.112 ; v2(38.37,31.31) 38.757,31.31 39.017,31.05 40.994,31.05 41.1,31.156 41.1,31.868 ; U15.21@8.9,14.9 U15.21@9.4,15.4 ; U15.21@9.4,15.4 U15.21@9.9,15.9 ; v1(11.1,36.1) U10.15@11.6,35.6 ; U1.57@30.8,8.8 v5(31.4,8.2) ; v5(31.4,8.2) U1.57@31.6,8.4 ; U1.57@31.6,8.4 v5(32.68,9.48) U1.57@32.8,9.6
  Top Layer w0.2: v1(12.7,24) U26.4@13.525,24 ; 13.525,22.86 U26.6@13.525,23 ; v1(17.7,1.95) U27.3@18.437,1.95 ; U27.5@18.95,1.438 v1(18.95,0.7) 19.3,0.7 19.45,0.85 U27.6@19.45,1.438 ; v1(19.963,0.713) U27.7@19.963,1.45 ; U27.8@19.963,1.95 20.463,1.95 ; C4.2@36.94,8.055 37.445,8.055 37.6,8.21 v1(37.6,8.56) ; FL2.2@39.12,30.443 FL2.5@39.12,29.618 39.12,29.215 39.222,29.113 v1(39.222,28.839) 39.495,28.839 39.62,28.964 FL2.6@39.62,29.618
  Top Layer w0.3: C81.2@3.57,10.25 R67.2@4.87,10.25 7.66,10.25 7.94,10.53 15.11,10.53 15.625,11.045 R65.1@15.625,12.7 15.625,14.415 15.18,14.86 12.41,14.86 11.37,15.9 ; v1(4.9,7.65) C47.2@5.7,7.65 ; C78.2@9.45,18.4 v1(10.425,18.4) ; C77.2@9.45,19.8 v1(10.425,19.8) ; U4.2@10,6.604 v1(10.7,6.604) ; v1(11.35,5.625) U5.1@12,5.625 ; U5.7@13.6,6.275 v1(14.26,6.275) ; C82.2@14.55,17.3 v1(15.325,17.3) ; C48.2@15.4,4.675 v1(16.2,4.675) ; C49.2@15.4,8.525 v1(16.2,8.525) ; U12.3@16.65,27.075 17.165,27.075 17.4,26.84 v1(17.4,26.5) ; v1(17.7,4.4) C111.2@18.675,4.4 ; v1(25.6,28.8) C68.2@26.675,28.8
  Top Layer w0.4: v1(3.36,16.615) C79.2@4.06,16.615 C80.2@5.46,16.615 6.275,16.615 6.91,15.98 U15.1@7.15,15.98 ; v1(5.9,1.75) C51.2@7.1,1.75 ; C50.2@13.525,1 v1(14.3,1) ; C83.2@15.8,19.1 v1(16.75,19.1) ; C112.2@21.6,1.95 22.16,1.95 22.4,1.71 v1(22.4,1.4) ; SW1.1@22.2,16 v1(23.5,16) ; v1(22.28,35.01) 22.28,34.68 22.585,34.375 J2.5@24.03,34.375 ; v1(22.4,5.4) Y1.4@23.4,5.4 ; J2.9@24.03,31.835 v1(25.895,31.835) ; J2.3@24.03,35.645 v1(25.855,35.645) ; v1(24.5,19) C43.2@25.4,19 ; v1(24.7,9.75) 25.05,9.4 Y1.2@25.8,9.4 ; Y2.2@25.15,20.5 25.475,20.175 C43.2@25.475,19 ; v1(25.2,16.72) 25.475,16.995 C39.2@25.475,17.6 ; C14.1@25.225,11.2 v1(25.225,11.9) ; Y2.4@26.85,22.7 26.525,23.025 C42.2@26.525,24.2 v1(27.45,24.2) ; v2(33.8,27.125) 35.025,27.125 Y4.2@35.3,27.4 ; Y4.4@37.5,25.8 37.775,26.075 v2(39,26.075) ; SW3.1@40,35.7 v1(41.4,35.7) ; SW2.1@40.2,22.1 v1(41.5,22.1) ; v1(42.75,9.9) 41.8,9.9 C12.2@41.8,10.3 41.8,10.7 v1(42.75,10.7) ; v1(42.75,12.3) 41.8,12.3 C13.2@41.8,12.7 41.8,13.1 v1(42.75,13.1) ; v1(43.6,31.8) J4.3@43.6,33.3 J4.3@43.625,33.325 ; v1(46.55,31.8) J4.2@46.55,33.3 46.575,33.325 TP34.1@46.575,35.6 ; C110.2@47.6,28.465 v1(47.6,29.225) ; TP10.1@50.862,12.65 v1(50.862,13.465)
  Top Layer w0.5: v1(12.04,21.46) 12.1,21.4 C86.1@13.084,21.4 13.084,22.284 13.525,22.725 13.525,22.86
  Top Layer w0.6: C67.2@51.625,28.69 A1.2@52.525,28.69
  Top Layer w0.9: 52.135,30.735 A1.3@52.615,30.735
  IN1-GND w0.15: 22.625,0.432 31.783,0.432 ; 41.02,39.568 41.49,39.568
  IN2 w0.15: 41.02,39.568 41.49,39.568
  IN4-GND w0.15: 22.625,0.432 31.783,0.432 ; 41.02,39.568 41.49,39.568
  Bottom Layer w0.15: 41.02,39.543 41.49,39.543
  Bottom Layer w0.3: C66.2@40.525,32.3 v1(41.4,32.3) ; C65.2@40.525,33.7 v1(41.4,33.7)
  Bottom Layer w0.4: v1(17.4,26.5) C75.2@17.4,27.4 ; v1(19.135,13.51) J17.19@19.135,14.285 ; C113.2@21.325,1.405 21.33,1.4 v1(22.4,1.4) ; J17.20@21.865,14.285 v1(23.39,14.285) ; v1(22.54,6.9) C15.1@23.584,6.9 ; v1(24.7,21.6) C37.2@25.475,21.6 ; v1(25.2,16.72) C38.2@25.2,17.6 ; R32.1@26.525,25.3 R33.1@26.525,26.6 v1(26.525,27.3) ; C41.2@28.675,16.89 v1(28.675,17.59) C40.2@28.675,18.29 ; v1(28.675,18.99) U21.1@28.675,19.695 U21.2@28.675,20.965 ; U21.3@28.675,22.235 U21.4@28.675,23.505 v1(28.675,24.21) ; C36.2@30.875,24.9 C18.2@30.875,26.3 v1(30.875,27) ; v1(35.3,24.8) C59.2@35.3,26.075 ; v1(36.72,24.83) 36.9,25.01 C60.2@36.9,25.8 ; C98.2@37.125,19.7 37.125,19.075 v1(37.2,19) ; C44.1@37.125,21.5 v1(37.9,21.5) ; C46.1@37.125,23.2 37.79,23.2 v1(37.9,23.09) ; v1(42.75,12.3) 41.8,12.3 C11.2@41.8,12.7 41.8,13.1 v1(42.75,13.1) ; v1(50.865,16.05) J18.12@50.865,16.825 ; J18.2@50.865,23.175 v1(50.865,23.95)
  other v1: 20.599,6.399 18.944,10.309 22.63,11.101 8.9,14.125 25.247,14.851 8.125,14.9 9.675,14.9 8.9,15.675 7.41,18.9 14.02,22.47 12.7,23 42.45,25.2 32.897,30.975 34.504,30.975 31.375,32.496 32.897,32.496 34.504,32.496 36.025,32.496 17.91,33.45 31.375,34.104 32.897,34.104 34.504,34.104 36.025,34.104 19.59,34.2 11.1,35.325 32.897,35.625 34.504,35.625 10.325,36.1 11.875,36.1 11.1,36.875 19.8,37.26 29.268,37.982
  other v2: 24.075,0.9 26.775,0.9 9.2,2.1 12.8,2.1 13.3,2.1 24.075,2.2 34.7,2.35 9.2,2.6 9.2,3.1 13.3,3.1 25.3,6.7 25.9,7.6 26.5,7.6 25.3,12.8 17.49,18.08 31.9,20.1 20.05,20.7 31.4,21.6 31.9,21.6 30.9,22.1 31.4,22.1 30.4,22.6 18.7,23.3 5.8,25.2 23.425,25.3 33.443,27.979 35.897,28.325 32.293,28.554 18.425,31.5 38.34,34.3 30.375,39.1
  other v4: 29.7,0.9 32.075,2.31 38.8,2.5 37.4,2.775 33.025,3.61 35.925,3.7 24.075,5 34.7,5.875 40.3,5.9 41.9,5.9 39.1,9.2 37.325,9.3 34.7,9.725 27.475,11.4 30.3,11.7 27.3,12.875 32.416,13.7 35.325,14.2 31.925,15.5 16.5,24.6 16.425,25.9 33.8,27.4 33.875,29.9 37.725,29.9 5.8,31.325 18.6,31.375 19.9,31.375 14.6,31.7 12.725,32.7 30.4,33.325 12.75,35.3 18.325,35.3 14.2,35.575 15.5,35.575 32.725,36.6 35.375,36.6 37.825,37.79 30,38.9 33.375,39.1 37.825,39.14
  other v5: 30.12,5.8 31.4,5.8 32.68,5.8 29,6.92 31.4,6.92 33.8,6.92 29,8.2 30.12,8.2 32.68,8.2 33.8,8.2 29,9.48 31.4,9.48 33.8,9.48 30.12,10.6 31.4,10.6 32.68,10.6
  other v6: 28.1,20.09 34.49,21.29 28.15,21.55 28.8,22.53
  other v7: 37.1,14.025
IRQ_MSP432_SSM: J17.16 J19.9 U2.H8 | length 38.2
  IN1-GND w0.1: v2(32.9,23.1) 33.094,23.294 v3(33.378,23.294)
  IN1-GND w0.2: v3(48.19,18.95) v2(48.54,18.95)
  IN2 w0.1: v1(23.4,16.825) 23.96,16.265 23.96,15.69 24.362,15.288 32.588,15.288 35.65,18.35 v3(36,18.35) 36.4,18.75 36.4,19.331 36.84,19.771 36.84,22.45 35.71,23.58 34.01,23.58 33.93,23.5 33.584,23.5 v3(33.378,23.294)
  IN3-POWER w0.1: v3(36,18.35) 37.232,18.35 37.832,18.95 v3(48.19,18.95)
  Bottom Layer w0.15: J17.16@21.865,16.825 v1(23.4,16.825)
ISENSE+_6: JP30.2 Q7.A1 R68.2 TP21.1 | length 9.1
  Top Layer w0.2: Q7.A1@23.4,24.35 23.62,24.35 23.8,24.17 23.8,23.75 23.425,23.375 R68.2@23.425,23 ; TP21.1@23.425,21.3 v1(23.425,22.3)
  Top Layer w0.5: v1(23.425,22.3) R68.2@23.425,23
  IN2 w0.5: JP30.2@23,27.7 23,26.3 23.425,25.875 v1(23.425,22.3)
ISENSE-: C70.1 C71.2 J18.1 JP19.1 JP30.1 TP20.1 U10.1 U10.6 | length 65.9
  Top Layer w0.15: JP19.1@7.3,38.1 8.3,38.1 TP20.1@9.3,39.1 10.1,38.3 U10.6@10.1,37.75
  Top Layer w0.2: U10.1@12.75,36.85 v1(12.75,37.81)
  IN3-POWER w0.4: JP30.1@23,29.7 25.83,29.7 27.83,27.7 41.15,27.7 43.15,25.7 v1(43.15,25.15)
  Bottom Layer w0.4: C70.1@12.75,36.9 12.82,36.83 13.43,36.83 13.635,36.625 C71.2@14.2,36.625 ; v1(43.15,25.15) 45.125,23.175 J18.1@48.135,23.175
  Bottom Layer w0.6: JP19.1@7.3,38.1 8.525,39.325 12.4,39.325 ; C70.1@12.75,36.9 v1(12.75,37.81) 12.75,38.975 ; JP30.1@23,29.7 25.15,31.85 25.15,37.85 23.675,39.325 13.1,39.325 ; 12.4,39.325 12.75,38.975 ; 12.4,39.325 13.1,39.325 ; 12.75,38.975 13.1,39.325
JTAG_TDO_1: J2.6 U2.A3 | length 31.4
  Top Layer w0.1: v1(24.6,16.4) 25,16 27.033,16 28.075,17.042 28.075,19.443 29.232,20.6 U2.A3@29.4,20.6
  Top Layer w0.15: v1(26.295,34.375) J2.6@27.93,34.375
  IN2 w0.1: v1(24.6,16.4) 24.6,16.8 23.9,17.5 23.1,17.5 22,18.6 22,30.37 25.68,34.05 25.97,34.05 v1(26.295,34.375)
LBOOST_7: L7.2 U15.20 | length 4.6
  Top Layer w1: L7.2@3.79,19.52 5.38,19.52 7.505,17.395
MSP432_ACLK_OUT_2: TP12.1 U2.G7 | length 8.7
  IN1-GND w0.082: 32.65,22.85 33.499,22.85
  IN1-GND w0.1: v2(32.4,22.6) 32.65,22.85 ; 33.499,22.85 33.769,23.12 v3(34.3,23.12)
  IN1-GND w0.2: v3(40.2,23.5) v2(40.2,23.9)
  IN3-POWER w0.1: v3(34.3,23.12) 34.68,23.5 38.084,23.5 38.284,23.3 40,23.3 v3(40.2,23.5)
MSP432_BSL: J18.6 U2.A1 | length 32.2
  Top Layer w0.1: U2.A1@29.4,19.6 31.925,17.075 43.875,17.075 v1(44.1,17.3)
  Bottom Layer w0.125: v1(44.1,17.3) 47.1,14.3 50.9,14.3 52.4,15.8 52.4,20.3 52.065,20.635 J18.6@50.865,20.635
MSP432_BUTTON1_2: R34.2 R35.2 U2.H7 | length 9.2
  IN1-GND w0.1: v2(32.9,22.6) v3(33.9,22.6)
  IN3-POWER w0.1: v3(33.9,22.6) 34.3,22.2 35.484,22.2 36.584,21.1 39.225,21.1 v3(39.575,21.45)
  IN4-GND w0.2: v4(39.575,21.1) v3(39.575,21.45)
  Bottom Layer w0.15: R34.2@39.575,19.7 v4(39.575,21.1)
MSP432_HF_XIN_2: C43.1 U2.A5 Y2.3 | length 4.6
  Top Layer w0.1: Y2.3@26.85,20.5 28.05,20.5 29.15,21.6 U2.A5@29.4,21.6
  Top Layer w0.125: C43.1@26.525,19 26.525,20.175 Y2.3@26.85,20.5
MSP432_HF_XOUT_2: C42.1 U2.A6 Y2.1 | length 6.7
  Top Layer w0.1: Y2.1@25.15,22.7 25.15,22.15 25.55,21.75 27.75,21.75 28.1,22.1 U2.A6@29.4,22.1
  Top Layer w0.125: Y2.1@25.15,22.7 25.475,23.025 C42.1@25.475,24.2
MSP432_HSMCLK_OUT_2: TP14.1 U2.G9 | length 6.6
  Top Layer w0.1: TP14.1@29.22,27.76 29.22,24.88 30.1,24 32,24 U2.G9@32.4,23.6
MSP432_JTAG_TCK: JP1.1 R100.1 U2.A2 | length 18.1
  Top Layer w0.1: v1(24.6,15.7) 24.675,15.775 27.126,15.775 28.3,16.949 28.3,19.35 29.05,20.1 U2.A2@29.4,20.1
  Bottom Layer w0.125: JP1.1@21.215,7.736 22.011,7.736 22.656,8.381 R100.1@22.656,9.154 23.117,9.154 23.319,9.356 23.319,11.927 24.6,13.207 v1(24.6,15.7)
MSP432_LED1_2: CR1.2 U2.A9 | length 3.7
  Top Layer w0.1: CR1.2@26.445,25.3 27,25.3 28.7,23.6 U2.A9@29.4,23.6
MSP432_LED2_2: CR2.2 U2.B9 | length 5.3
  Top Layer w0.1: 26.85,26.6 27.15,26.3 27.15,25.532 27.982,24.7 29.05,24.7 29.9,23.85
  Top Layer w0.125: CR2.2@26.45,26.6 26.85,26.6 ; U2.B9@29.9,23.6 29.9,23.85
MSP432_LF_XIN_2: C44.2 U2.J6 Y3.1 | length 5
  Top Layer w0.1: U2.J6@33.4,22.1 36.23,22.1 v1(36.33,22.2) 36.6,21.93 Y3.1@36.6,21.05
  Bottom Layer w0.15: C44.2@36.075,21.5 36.075,21.945 v1(36.33,22.2)
MSP432_LF_XOUT_2: C46.2 U2.J7 Y3.2 | length 4.9
  Top Layer w0.1: U2.J7@33.4,22.6 35.65,22.6 v1(35.75,22.5) 36.05,22.5 36.6,23.05 Y3.2@36.6,23.55
  Bottom Layer w0.15: v1(35.75,22.5) 35.99,22.5 36.075,22.585 C46.2@36.075,23.2
MSP432_MCLK_OUT_2: TP13.1 U2.G8 | length 2.7
  IN1-GND w0.1: v2(32.4,23.1) 33,23.7 34.75,23.7 v2(34.85,23.6)
MSP432_SMCLK_OUT_2: TP16.1 U2.B5 | length 6.4
  Top Layer w0.125: v1(27.85,25.6) TP16.1@27.85,26.4
  IN1-GND w0.1: v3(28.7,21.6) v2(29.9,21.6)
  IN2 w0.1: v1(27.85,25.6) 28.1,25.35 28.1,23.266 28.7,22.666 v3(28.7,21.6)
MSP432_SSM_PWM1: J17.15 U2.B8 | length 17.1
  IN1-GND w0.1: v3(28.9,23.1) v2(29.9,23.1)
  IN3-POWER w0.1: v3(19.485,16.825) 18.6,17.71 18.6,19.611 19.154,20.165 19.581,20.165 20.1,20.684 20.1,21.883 21.517,23.3 28.7,23.3 v3(28.9,23.1)
  IN4-GND w0.2: v4(19.135,16.825) v3(19.485,16.825)
MSP432_SSM_PWM2: J17.17 U2.B7 | length 18.5
  IN1-GND w0.1: v3(29.4,22.6) v2(29.9,22.6)
  IN3-POWER w0.1: v3(19.485,15.555) 19.885,15.955 19.885,16.991 19.381,17.495 19.236,17.495 18.8,17.931 18.8,19.529 19.236,19.965 19.664,19.965 20.3,20.601 20.3,21.8 21.6,23.1 28.334,23.1 28.834,22.6 v3(29.4,22.6)
  IN4-GND w0.2: v4(19.135,15.555) v3(19.485,15.555)
MSP432_SSM_SPI_CLK: J17.12 J19.1 U2.C1 | length 26.7
  Top Layer w0.1: U2.C1@30.4,19.6 v2(30.4,19.1) 31.525,17.975 32.525,17.975 33.2,17.3 43.1,17.3 43.46,17.66 J19.1@43.46,18.95
  IN1-GND w0.1: v3(30.316,17.85) 29.9,18.266 29.9,18.666 30.334,19.1 v2(30.4,19.1)
  IN3-POWER w0.1: v1(23.39,19.365) 23.625,19.6 27.083,19.6 28.323,18.36 29.673,18.36 30.183,17.85 v3(30.316,17.85)
  Bottom Layer w0.15: J17.12@21.865,19.365 v1(23.39,19.365)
